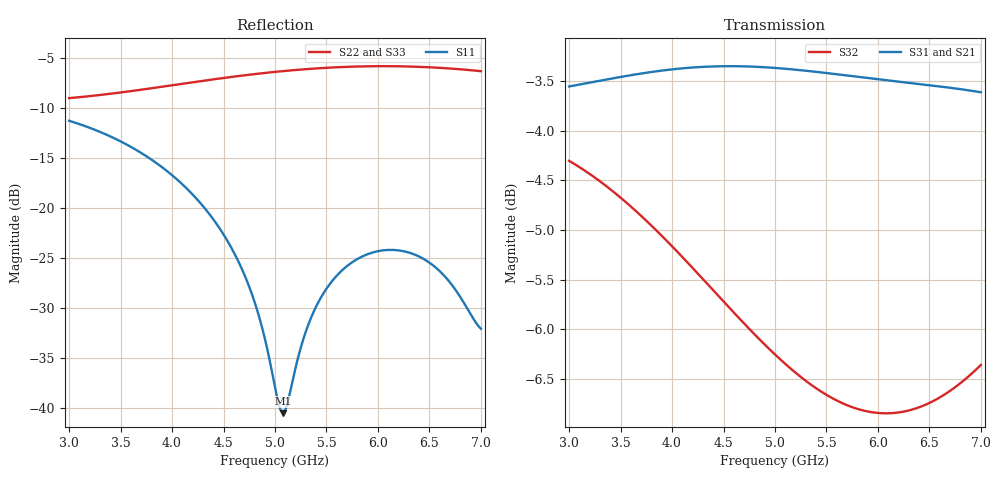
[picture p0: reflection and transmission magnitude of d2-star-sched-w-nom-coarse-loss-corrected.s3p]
! yapnr Order 0 prediction d2-star-sched-w-nom-coarse: predictions/D2/variants/d2-star-sched-w-nom/coarse_dense.s3p, loss-corrected
! substrate W-nom; coupon model OSHPARK-4L-FR408HR; correction: ratio (port line)
! |S21|, |S31| (and S12, S13) scaled, phases kept; 50 ohm, e^(+jwt)
# GHz S RI R 50
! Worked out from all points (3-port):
!   161 points, 3 GHz to 7 GHz, reference 50 ohm
!   strongest paths, dB at 3 GHz, 4 GHz, 5 GHz, 6 GHz, 7 GHz:
!     S31: -3.6, -3.4, -3.4, -3.5, -3.6
!     S21: -3.6, -3.4, -3.4, -3.5, -3.6
!     S32: -4.3, -5.2, -6.3, -6.8, -6.4
!   lowest |S11| = -40.6 dB at 5.075 GHz (marker M1), VSWR 1.02, Z = 49.6 + j0.826 ohm
!   |S11| at or under -10 dB: start of sweep to end of sweep
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3  -0.0947 0.2546  -0.3596 -0.5587  -0.3596 -0.5587
   -0.3596 -0.5581  0.307 0.1731  -0.5772 -0.1949
   -0.3596 -0.5581  -0.5772 -0.1949  0.307 0.1731
3.6  0.00231 0.2011  -0.576 -0.3479  -0.576 -0.3479
     -0.5757 -0.3479  0.3786 -0.0506  -0.5607 0.1395
     -0.5757 -0.3479  -0.5607 0.1395  0.3786 -0.0506
4.35  0.0429 0.0844  -0.678 0.0312  -0.678 0.0312
      -0.6787 0.03  0.2798 -0.3313  -0.3178 0.4214
      -0.6787 0.03  -0.3178 0.4214  0.2798 -0.3313
4.75  0.0231 0.0328  -0.6333 0.2424  -0.6333 0.2424
      -0.6351 0.2414  0.1557 -0.4342  -0.1505 0.4784
      -0.6351 0.2414  -0.1505 0.4784  0.1557 -0.4342
5  0.0024 0.0124  -0.5709 0.3628  -0.5709 0.3628
   -0.5734 0.3624  0.0624 -0.4725  -0.0485 0.4844
   -0.5734 0.3624  -0.0485 0.4844  0.0624 -0.4725
5.075  -0.0043 0.00833  -0.5476 0.3962  -0.5476 0.3962
       -0.5502 0.396  0.033 -0.4796  -0.0191 0.4825
       -0.5502 0.396  -0.0191 0.4825  0.033 -0.4796
5.425  -0.034 0.000947  -0.414 0.5297  -0.414 0.5297
       -0.4169 0.5309  -0.1067 -0.4853  0.1086 0.4544
       -0.4169 0.5309  0.1086 0.4544  -0.1067 -0.4853
5.875  -0.0567 0.0116  -0.198 0.6373  -0.198 0.6373
       -0.1999 0.6403  -0.274 -0.4278  0.2476 0.383
       -0.1999 0.6403  0.2476 0.383  -0.274 -0.4278
6.475  -0.048 0.0251  0.1225 0.6502  0.1225 0.6502
       0.1239 0.6535  -0.4301 -0.2614  0.3911 0.2415
       0.1239 0.6535  0.3911 0.2415  -0.4301 -0.2614
7  -0.0248 -0.00046  0.3832 0.5336  0.3832 0.5336
   0.3867 0.5342  -0.4745 -0.0758  0.4753 0.074
   0.3867 0.5342  0.4753 0.074  -0.4745 -0.0758
